VERSION 5.7 ;
  NOWIREEXTENSIONATPIN ON ;
  DIVIDERCHAR "/" ;
  BUSBITCHARS "[]" ;
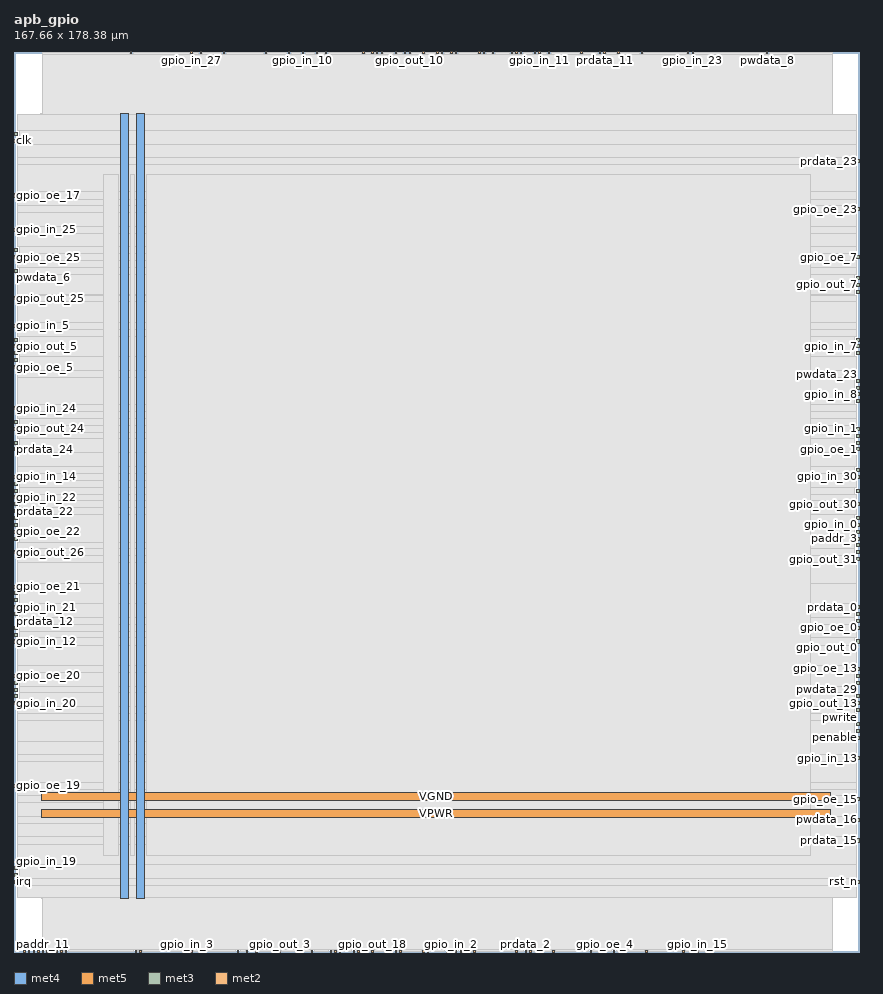
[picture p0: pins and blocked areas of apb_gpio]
MACRO apb_gpio
  CLASS BLOCK ;
  FOREIGN apb_gpio ;
  ORIGIN 0.000 0.000 ;
  SIZE 167.660 BY 178.380 ;
  PIN VGND
    DIRECTION INOUT ;
    USE GROUND ;
    PORT
      LAYER met4 ;
        RECT 24.340 10.640 25.940 166.160 ;
    END
    PORT
      LAYER met5 ;
        RECT 5.520 30.030 161.920 31.630 ;
    END
  END VGND
  PIN VPWR
    DIRECTION INOUT ;
    USE POWER ;
    PORT
      LAYER met4 ;
        RECT 21.040 10.640 22.640 166.160 ;
    END
    PORT
      LAYER met5 ;
        RECT 5.520 26.730 161.920 28.330 ;
    END
  END VPWR
  PIN clk
    DIRECTION INPUT ;
    USE SIGNAL ;
    ANTENNAGATEAREA 1.286700 ;
    ANTENNADIFFAREA 0.434700 ;
    PORT
      LAYER met3 ;
        RECT 0.000 160.520 0.600 161.120 ;
    END
  END clk
  PIN gpio_in_0
    DIRECTION INPUT ;
    USE SIGNAL ;
    ANTENNAGATEAREA 0.647700 ;
    ANTENNADIFFAREA 0.434700 ;
    PORT
      LAYER met3 ;
        RECT 167.060 84.360 167.660 84.960 ;
    END
  END gpio_in_0
  PIN gpio_in_1
    DIRECTION INPUT ;
    USE SIGNAL ;
    ANTENNAGATEAREA 0.647700 ;
    ANTENNADIFFAREA 0.434700 ;
    PORT
      LAYER met3 ;
        RECT 167.060 103.400 167.660 104.000 ;
    END
  END gpio_in_1
  PIN gpio_in_10
    DIRECTION INPUT ;
    USE SIGNAL ;
    ANTENNAGATEAREA 0.647700 ;
    ANTENNADIFFAREA 0.434700 ;
    PORT
      LAYER met2 ;
        RECT 57.130 178.100 57.410 178.380 ;
    END
  END gpio_in_10
  PIN gpio_in_11
    DIRECTION INPUT ;
    USE SIGNAL ;
    ANTENNAGATEAREA 0.647700 ;
    ANTENNADIFFAREA 0.434700 ;
    PORT
      LAYER met2 ;
        RECT 104.050 178.100 104.330 178.380 ;
    END
  END gpio_in_11
  PIN gpio_in_12
    DIRECTION INPUT ;
    USE SIGNAL ;
    ANTENNAGATEAREA 0.647700 ;
    ANTENNADIFFAREA 0.434700 ;
    PORT
      LAYER met3 ;
        RECT 0.000 61.240 0.600 61.840 ;
    END
  END gpio_in_12
  PIN gpio_in_13
    DIRECTION INPUT ;
    USE SIGNAL ;
    ANTENNAGATEAREA 0.647700 ;
    ANTENNADIFFAREA 0.434700 ;
    PORT
      LAYER met3 ;
        RECT 167.060 38.120 167.660 38.720 ;
    END
  END gpio_in_13
  PIN gpio_in_14
    DIRECTION INPUT ;
    USE SIGNAL ;
    ANTENNAGATEAREA 0.647700 ;
    ANTENNADIFFAREA 0.434700 ;
    PORT
      LAYER met3 ;
        RECT 0.000 93.880 0.600 94.480 ;
    END
  END gpio_in_14
  PIN gpio_in_15
    DIRECTION INPUT ;
    USE SIGNAL ;
    ANTENNAGATEAREA 0.647700 ;
    ANTENNADIFFAREA 0.434700 ;
    PORT
      LAYER met2 ;
        RECT 135.330 0.000 135.610 0.280 ;
    END
  END gpio_in_15
  PIN gpio_in_16
    DIRECTION INPUT ;
    USE SIGNAL ;
    ANTENNAGATEAREA 0.647700 ;
    ANTENNADIFFAREA 0.434700 ;
    PORT
      LAYER met3 ;
        RECT 0.000 121.080 0.600 121.680 ;
    END
  END gpio_in_16
  PIN gpio_in_17
    DIRECTION INPUT ;
    USE SIGNAL ;
    ANTENNAGATEAREA 0.647700 ;
    ANTENNADIFFAREA 0.434700 ;
    PORT
      LAYER met3 ;
        RECT 0.000 161.880 0.600 162.480 ;
    END
  END gpio_in_17
  PIN gpio_in_18
    DIRECTION INPUT ;
    USE SIGNAL ;
    ANTENNAGATEAREA 0.647700 ;
    ANTENNADIFFAREA 0.434700 ;
    PORT
      LAYER met2 ;
        RECT 58.970 0.000 59.250 0.280 ;
    END
  END gpio_in_18
  PIN gpio_in_19
    DIRECTION INPUT ;
    USE SIGNAL ;
    ANTENNAGATEAREA 0.647700 ;
    ANTENNADIFFAREA 0.434700 ;
    PORT
      LAYER met3 ;
        RECT 0.000 16.360 0.600 16.960 ;
    END
  END gpio_in_19
  PIN gpio_in_2
    DIRECTION INPUT ;
    USE SIGNAL ;
    ANTENNAGATEAREA 0.647700 ;
    ANTENNADIFFAREA 0.434700 ;
    PORT
      LAYER met2 ;
        RECT 86.570 0.000 86.850 0.280 ;
    END
  END gpio_in_2
  PIN gpio_in_20
    DIRECTION INPUT ;
    USE SIGNAL ;
    ANTENNAGATEAREA 0.647700 ;
    ANTENNADIFFAREA 0.434700 ;
    PORT
      LAYER met3 ;
        RECT 0.000 49.000 0.600 49.600 ;
    END
  END gpio_in_20
  PIN gpio_in_21
    DIRECTION INPUT ;
    USE SIGNAL ;
    ANTENNAGATEAREA 0.647700 ;
    ANTENNADIFFAREA 0.434700 ;
    PORT
      LAYER met3 ;
        RECT 0.000 68.040 0.600 68.640 ;
    END
  END gpio_in_21
  PIN gpio_in_22
    DIRECTION INPUT ;
    USE SIGNAL ;
    ANTENNAGATEAREA 0.647700 ;
    ANTENNADIFFAREA 0.434700 ;
    PORT
      LAYER met3 ;
        RECT 0.000 91.160 0.600 91.760 ;
    END
  END gpio_in_22
  PIN gpio_in_23
    DIRECTION INPUT ;
    USE SIGNAL ;
    ANTENNAGATEAREA 0.647700 ;
    ANTENNADIFFAREA 0.434700 ;
    PORT
      LAYER met2 ;
        RECT 134.410 178.100 134.690 178.380 ;
    END
  END gpio_in_23
  PIN gpio_in_24
    DIRECTION INPUT ;
    USE SIGNAL ;
    ANTENNAGATEAREA 0.647700 ;
    ANTENNADIFFAREA 0.434700 ;
    PORT
      LAYER met3 ;
        RECT 0.000 107.480 0.600 108.080 ;
    END
  END gpio_in_24
  PIN gpio_in_25
    DIRECTION INPUT ;
    USE SIGNAL ;
    ANTENNAGATEAREA 0.647700 ;
    ANTENNADIFFAREA 0.434700 ;
    PORT
      LAYER met3 ;
        RECT 0.000 142.840 0.600 143.440 ;
    END
  END gpio_in_25
  PIN gpio_in_26
    DIRECTION INPUT ;
    USE SIGNAL ;
    ANTENNAGATEAREA 0.647700 ;
    ANTENNADIFFAREA 0.434700 ;
    PORT
      LAYER met3 ;
        RECT 0.000 89.800 0.600 90.400 ;
    END
  END gpio_in_26
  PIN gpio_in_27
    DIRECTION INPUT ;
    USE SIGNAL ;
    ANTENNAGATEAREA 0.647700 ;
    ANTENNADIFFAREA 0.434700 ;
    PORT
      LAYER met2 ;
        RECT 35.050 178.100 35.330 178.380 ;
    END
  END gpio_in_27
  PIN gpio_in_28
    DIRECTION INPUT ;
    USE SIGNAL ;
    ANTENNAGATEAREA 0.647700 ;
    ANTENNADIFFAREA 0.434700 ;
    PORT
      LAYER met2 ;
        RECT 84.730 178.100 85.010 178.380 ;
    END
  END gpio_in_28
  PIN gpio_in_29
    DIRECTION INPUT ;
    USE SIGNAL ;
    ANTENNAGATEAREA 0.647700 ;
    ANTENNADIFFAREA 0.434700 ;
    PORT
      LAYER met2 ;
        RECT 86.570 178.100 86.850 178.380 ;
    END
  END gpio_in_29
  PIN gpio_in_3
    DIRECTION INPUT ;
    USE SIGNAL ;
    ANTENNAGATEAREA 0.647700 ;
    ANTENNADIFFAREA 0.434700 ;
    PORT
      LAYER met2 ;
        RECT 34.130 0.000 34.410 0.280 ;
    END
  END gpio_in_3
  PIN gpio_in_30
    DIRECTION INPUT ;
    USE SIGNAL ;
    ANTENNAGATEAREA 0.647700 ;
    ANTENNADIFFAREA 0.434700 ;
    PORT
      LAYER met3 ;
        RECT 167.060 93.880 167.660 94.480 ;
    END
  END gpio_in_30
  PIN gpio_in_31
    DIRECTION INPUT ;
    USE SIGNAL ;
    ANTENNAGATEAREA 0.647700 ;
    ANTENNADIFFAREA 0.434700 ;
    PORT
      LAYER met2 ;
        RECT 75.530 0.000 75.810 0.280 ;
    END
  END gpio_in_31
  PIN gpio_in_4
    DIRECTION INPUT ;
    USE SIGNAL ;
    ANTENNAGATEAREA 0.647700 ;
    ANTENNADIFFAREA 0.434700 ;
    PORT
      LAYER met2 ;
        RECT 114.170 0.000 114.450 0.280 ;
    END
  END gpio_in_4
  PIN gpio_in_5
    DIRECTION INPUT ;
    USE SIGNAL ;
    ANTENNAGATEAREA 0.647700 ;
    ANTENNADIFFAREA 0.434700 ;
    PORT
      LAYER met3 ;
        RECT 0.000 123.800 0.600 124.400 ;
    END
  END gpio_in_5
  PIN gpio_in_6
    DIRECTION INPUT ;
    USE SIGNAL ;
    ANTENNAGATEAREA 0.647700 ;
    ANTENNADIFFAREA 0.434700 ;
    PORT
      LAYER met2 ;
        RECT 76.450 0.000 76.730 0.280 ;
    END
  END gpio_in_6
  PIN gpio_in_7
    DIRECTION INPUT ;
    USE SIGNAL ;
    ANTENNAGATEAREA 0.647700 ;
    ANTENNADIFFAREA 0.434700 ;
    PORT
      LAYER met3 ;
        RECT 167.060 119.720 167.660 120.320 ;
    END
  END gpio_in_7
  PIN gpio_in_8
    DIRECTION INPUT ;
    USE SIGNAL ;
    ANTENNAGATEAREA 0.647700 ;
    ANTENNADIFFAREA 0.434700 ;
    PORT
      LAYER met3 ;
        RECT 167.060 110.200 167.660 110.800 ;
    END
  END gpio_in_8
  PIN gpio_in_9
    DIRECTION INPUT ;
    USE SIGNAL ;
    ANTENNAGATEAREA 0.647700 ;
    ANTENNADIFFAREA 0.434700 ;
    PORT
      LAYER met2 ;
        RECT 90.250 0.000 90.530 0.280 ;
    END
  END gpio_in_9
  PIN gpio_oe_0
    DIRECTION OUTPUT ;
    USE SIGNAL ;
    ANTENNAGATEAREA 0.434700 ;
    ANTENNADIFFAREA 1.137600 ;
    PORT
      LAYER met3 ;
        RECT 167.060 63.960 167.660 64.560 ;
    END
  END gpio_oe_0
  PIN gpio_oe_1
    DIRECTION OUTPUT ;
    USE SIGNAL ;
    ANTENNAGATEAREA 0.434700 ;
    ANTENNADIFFAREA 1.137600 ;
    PORT
      LAYER met3 ;
        RECT 167.060 100.680 167.660 101.280 ;
    END
  END gpio_oe_1
  PIN gpio_oe_10
    DIRECTION OUTPUT ;
    USE SIGNAL ;
    ANTENNAGATEAREA 0.434700 ;
    ANTENNADIFFAREA 1.137600 ;
    PORT
      LAYER met2 ;
        RECT 71.850 178.100 72.130 178.380 ;
    END
  END gpio_oe_10
  PIN gpio_oe_11
    DIRECTION OUTPUT ;
    USE SIGNAL ;
    ANTENNAGATEAREA 0.434700 ;
    ANTENNADIFFAREA 1.137600 ;
    PORT
      LAYER met2 ;
        RECT 116.010 178.100 116.290 178.380 ;
    END
  END gpio_oe_11
  PIN gpio_oe_12
    DIRECTION OUTPUT ;
    USE SIGNAL ;
    ANTENNAGATEAREA 0.434700 ;
    ANTENNADIFFAREA 1.137600 ;
    PORT
      LAYER met3 ;
        RECT 0.000 69.400 0.600 70.000 ;
    END
  END gpio_oe_12
  PIN gpio_oe_13
    DIRECTION OUTPUT ;
    USE SIGNAL ;
    ANTENNAGATEAREA 0.434700 ;
    ANTENNADIFFAREA 1.137600 ;
    PORT
      LAYER met3 ;
        RECT 167.060 55.800 167.660 56.400 ;
    END
  END gpio_oe_13
  PIN gpio_oe_14
    DIRECTION OUTPUT ;
    USE SIGNAL ;
    ANTENNAGATEAREA 0.434700 ;
    ANTENNADIFFAREA 1.137600 ;
    PORT
      LAYER met2 ;
        RECT 98.530 178.100 98.810 178.380 ;
    END
  END gpio_oe_14
  PIN gpio_oe_15
    DIRECTION OUTPUT ;
    USE SIGNAL ;
    ANTENNAGATEAREA 0.434700 ;
    ANTENNADIFFAREA 1.137600 ;
    PORT
      LAYER met3 ;
        RECT 167.060 29.960 167.660 30.560 ;
    END
  END gpio_oe_15
  PIN gpio_oe_16
    DIRECTION OUTPUT ;
    USE SIGNAL ;
    ANTENNAGATEAREA 0.434700 ;
    ANTENNADIFFAREA 1.137600 ;
    PORT
      LAYER met2 ;
        RECT 75.530 178.100 75.810 178.380 ;
    END
  END gpio_oe_16
  PIN gpio_oe_17
    DIRECTION OUTPUT ;
    USE SIGNAL ;
    ANTENNAGATEAREA 0.434700 ;
    ANTENNADIFFAREA 1.137600 ;
    PORT
      LAYER met3 ;
        RECT 0.000 149.640 0.600 150.240 ;
    END
  END gpio_oe_17
  PIN gpio_oe_18
    DIRECTION OUTPUT ;
    USE SIGNAL ;
    ANTENNAGATEAREA 0.434700 ;
    ANTENNADIFFAREA 1.137600 ;
    PORT
      LAYER met2 ;
        RECT 63.570 0.000 63.850 0.280 ;
    END
  END gpio_oe_18
  PIN gpio_oe_19
    DIRECTION OUTPUT ;
    USE SIGNAL ;
    ANTENNAGATEAREA 0.434700 ;
    ANTENNADIFFAREA 1.137600 ;
    PORT
      LAYER met3 ;
        RECT 0.000 32.680 0.600 33.280 ;
    END
  END gpio_oe_19
  PIN gpio_oe_2
    DIRECTION OUTPUT ;
    USE SIGNAL ;
    ANTENNAGATEAREA 0.434700 ;
    ANTENNADIFFAREA 1.137600 ;
    PORT
      LAYER met3 ;
        RECT 167.060 65.320 167.660 65.920 ;
    END
  END gpio_oe_2
  PIN gpio_oe_20
    DIRECTION OUTPUT ;
    USE SIGNAL ;
    ANTENNAGATEAREA 0.434700 ;
    ANTENNADIFFAREA 1.137600 ;
    PORT
      LAYER met3 ;
        RECT 0.000 54.440 0.600 55.040 ;
    END
  END gpio_oe_20
  PIN gpio_oe_21
    DIRECTION OUTPUT ;
    USE SIGNAL ;
    ANTENNAGATEAREA 0.434700 ;
    ANTENNADIFFAREA 1.137600 ;
    PORT
      LAYER met3 ;
        RECT 0.000 72.120 0.600 72.720 ;
    END
  END gpio_oe_21
  PIN gpio_oe_22
    DIRECTION OUTPUT ;
    USE SIGNAL ;
    ANTENNAGATEAREA 0.434700 ;
    ANTENNADIFFAREA 1.137600 ;
    PORT
      LAYER met3 ;
        RECT 0.000 83.000 0.600 83.600 ;
    END
  END gpio_oe_22
  PIN gpio_oe_23
    DIRECTION OUTPUT ;
    USE SIGNAL ;
    ANTENNAGATEAREA 0.434700 ;
    ANTENNADIFFAREA 1.137600 ;
    PORT
      LAYER met3 ;
        RECT 167.060 146.920 167.660 147.520 ;
    END
  END gpio_oe_23
  PIN gpio_oe_24
    DIRECTION OUTPUT ;
    USE SIGNAL ;
    ANTENNAGATEAREA 0.434700 ;
    ANTENNADIFFAREA 1.137600 ;
    PORT
      LAYER met3 ;
        RECT 0.000 99.320 0.600 99.920 ;
    END
  END gpio_oe_24
  PIN gpio_oe_25
    DIRECTION OUTPUT ;
    USE SIGNAL ;
    ANTENNAGATEAREA 0.434700 ;
    ANTENNADIFFAREA 1.137600 ;
    PORT
      LAYER met3 ;
        RECT 0.000 137.400 0.600 138.000 ;
    END
  END gpio_oe_25
  PIN gpio_oe_26
    DIRECTION OUTPUT ;
    USE SIGNAL ;
    ANTENNAGATEAREA 0.434700 ;
    ANTENNADIFFAREA 1.137600 ;
    PORT
      LAYER met3 ;
        RECT 0.000 87.080 0.600 87.680 ;
    END
  END gpio_oe_26
  PIN gpio_oe_27
    DIRECTION OUTPUT ;
    USE SIGNAL ;
    ANTENNAGATEAREA 0.434700 ;
    ANTENNADIFFAREA 1.137600 ;
    PORT
      LAYER met2 ;
        RECT 54.370 178.100 54.650 178.380 ;
    END
  END gpio_oe_27
  PIN gpio_oe_28
    DIRECTION OUTPUT ;
    USE SIGNAL ;
    ANTENNAGATEAREA 0.434700 ;
    ANTENNADIFFAREA 1.137600 ;
    PORT
      LAYER met3 ;
        RECT 167.060 108.840 167.660 109.440 ;
    END
  END gpio_oe_28
  PIN gpio_oe_29
    DIRECTION OUTPUT ;
    USE SIGNAL ;
    ANTENNAGATEAREA 0.434700 ;
    ANTENNADIFFAREA 1.137600 ;
    PORT
      LAYER met2 ;
        RECT 92.090 178.100 92.370 178.380 ;
    END
  END gpio_oe_29
  PIN gpio_oe_3
    DIRECTION OUTPUT ;
    USE SIGNAL ;
    ANTENNAGATEAREA 0.434700 ;
    ANTENNADIFFAREA 1.137600 ;
    PORT
      LAYER met2 ;
        RECT 44.250 0.000 44.530 0.280 ;
    END
  END gpio_oe_3
  PIN gpio_oe_30
    DIRECTION OUTPUT ;
    USE SIGNAL ;
    ANTENNAGATEAREA 0.434700 ;
    ANTENNADIFFAREA 1.137600 ;
    PORT
      LAYER met3 ;
        RECT 167.060 85.720 167.660 86.320 ;
    END
  END gpio_oe_30
  PIN gpio_oe_31
    DIRECTION OUTPUT ;
    USE SIGNAL ;
    ANTENNAGATEAREA 0.434700 ;
    ANTENNADIFFAREA 1.137600 ;
    PORT
      LAYER met2 ;
        RECT 88.410 0.000 88.690 0.280 ;
    END
  END gpio_oe_31
  PIN gpio_oe_4
    DIRECTION OUTPUT ;
    USE SIGNAL ;
    ANTENNAGATEAREA 0.434700 ;
    ANTENNADIFFAREA 1.137600 ;
    PORT
      LAYER met2 ;
        RECT 116.930 0.000 117.210 0.280 ;
    END
  END gpio_oe_4
  PIN gpio_oe_5
    DIRECTION OUTPUT ;
    USE SIGNAL ;
    ANTENNAGATEAREA 0.434700 ;
    ANTENNADIFFAREA 1.137600 ;
    PORT
      LAYER met3 ;
        RECT 0.000 115.640 0.600 116.240 ;
    END
  END gpio_oe_5
  PIN gpio_oe_6
    DIRECTION OUTPUT ;
    USE SIGNAL ;
    ANTENNAGATEAREA 0.434700 ;
    ANTENNADIFFAREA 1.137600 ;
    PORT
      LAYER met2 ;
        RECT 81.050 0.000 81.330 0.280 ;
    END
  END gpio_oe_6
  PIN gpio_oe_7
    DIRECTION OUTPUT ;
    USE SIGNAL ;
    ANTENNAGATEAREA 0.434700 ;
    ANTENNADIFFAREA 1.137600 ;
    PORT
      LAYER met3 ;
        RECT 167.060 137.400 167.660 138.000 ;
    END
  END gpio_oe_7
  PIN gpio_oe_8
    DIRECTION OUTPUT ;
    USE SIGNAL ;
    ANTENNAGATEAREA 0.434700 ;
    ANTENNADIFFAREA 1.137600 ;
    PORT
      LAYER met3 ;
        RECT 167.060 121.080 167.660 121.680 ;
    END
  END gpio_oe_8
  PIN gpio_oe_9
    DIRECTION OUTPUT ;
    USE SIGNAL ;
    ANTENNAGATEAREA 0.434700 ;
    ANTENNADIFFAREA 1.137600 ;
    PORT
      LAYER met2 ;
        RECT 99.450 0.000 99.730 0.280 ;
    END
  END gpio_oe_9
  PIN gpio_out_0
    DIRECTION OUTPUT ;
    USE SIGNAL ;
    ANTENNAGATEAREA 0.434700 ;
    ANTENNADIFFAREA 1.137600 ;
    PORT
      LAYER met3 ;
        RECT 167.060 61.240 167.660 61.840 ;
    END
  END gpio_out_0
  PIN gpio_out_1
    DIRECTION OUTPUT ;
    USE SIGNAL ;
    ANTENNAGATEAREA 0.434700 ;
    ANTENNADIFFAREA 1.137600 ;
    PORT
      LAYER met3 ;
        RECT 167.060 99.320 167.660 99.920 ;
    END
  END gpio_out_1
  PIN gpio_out_10
    DIRECTION OUTPUT ;
    USE SIGNAL ;
    ANTENNAGATEAREA 0.434700 ;
    ANTENNADIFFAREA 1.137600 ;
    PORT
      LAYER met2 ;
        RECT 78.290 178.100 78.570 178.380 ;
    END
  END gpio_out_10
  PIN gpio_out_11
    DIRECTION OUTPUT ;
    USE SIGNAL ;
    ANTENNAGATEAREA 0.434700 ;
    ANTENNADIFFAREA 1.137600 ;
    PORT
      LAYER met2 ;
        RECT 119.690 178.100 119.970 178.380 ;
    END
  END gpio_out_11
  PIN gpio_out_12
    DIRECTION OUTPUT ;
    USE SIGNAL ;
    ANTENNAGATEAREA 0.434700 ;
    ANTENNADIFFAREA 1.137600 ;
    PORT
      LAYER met2 ;
        RECT 68.170 0.000 68.450 0.280 ;
    END
  END gpio_out_12
  PIN gpio_out_13
    DIRECTION OUTPUT ;
    USE SIGNAL ;
    ANTENNAGATEAREA 0.434700 ;
    ANTENNADIFFAREA 1.137600 ;
    PORT
      LAYER met3 ;
        RECT 167.060 49.000 167.660 49.600 ;
    END
  END gpio_out_13
  PIN gpio_out_14
    DIRECTION OUTPUT ;
    USE SIGNAL ;
    ANTENNAGATEAREA 0.434700 ;
    ANTENNADIFFAREA 1.137600 ;
    PORT
      LAYER met2 ;
        RECT 81.050 178.100 81.330 178.380 ;
    END
  END gpio_out_14
  PIN gpio_out_15
    DIRECTION OUTPUT ;
    USE SIGNAL ;
    ANTENNAGATEAREA 0.434700 ;
    ANTENNADIFFAREA 1.137600 ;
    PORT
      LAYER met2 ;
        RECT 132.570 0.000 132.850 0.280 ;
    END
  END gpio_out_15
  PIN gpio_out_16
    DIRECTION OUTPUT ;
    USE SIGNAL ;
    ANTENNAGATEAREA 0.434700 ;
    ANTENNADIFFAREA 1.137600 ;
    PORT
      LAYER met2 ;
        RECT 70.930 178.100 71.210 178.380 ;
    END
  END gpio_out_16
  PIN gpio_out_17
    DIRECTION OUTPUT ;
    USE SIGNAL ;
    ANTENNAGATEAREA 0.434700 ;
    ANTENNADIFFAREA 1.137600 ;
    PORT
      LAYER met2 ;
        RECT 36.890 178.100 37.170 178.380 ;
    END
  END gpio_out_17
  PIN gpio_out_18
    DIRECTION OUTPUT ;
    USE SIGNAL ;
    ANTENNAGATEAREA 0.434700 ;
    ANTENNADIFFAREA 1.137600 ;
    PORT
      LAYER met2 ;
        RECT 70.930 0.000 71.210 0.280 ;
    END
  END gpio_out_18
  PIN gpio_out_19
    DIRECTION OUTPUT ;
    USE SIGNAL ;
    ANTENNAGATEAREA 0.434700 ;
    ANTENNADIFFAREA 1.137600 ;
    PORT
      LAYER met2 ;
        RECT 35.050 0.000 35.330 0.280 ;
    END
  END gpio_out_19
  PIN gpio_out_2
    DIRECTION OUTPUT ;
    USE SIGNAL ;
    ANTENNAGATEAREA 0.434700 ;
    ANTENNADIFFAREA 1.137600 ;
    PORT
      LAYER met3 ;
        RECT 167.060 54.440 167.660 55.040 ;
    END
  END gpio_out_2
  PIN gpio_out_20
    DIRECTION OUTPUT ;
    USE SIGNAL ;
    ANTENNAGATEAREA 0.434700 ;
    ANTENNADIFFAREA 1.137600 ;
    PORT
      LAYER met3 ;
        RECT 0.000 51.720 0.600 52.320 ;
    END
  END gpio_out_20
  PIN gpio_out_21
    DIRECTION OUTPUT ;
    USE SIGNAL ;
    ANTENNAGATEAREA 0.434700 ;
    ANTENNADIFFAREA 1.137600 ;
    PORT
      LAYER met3 ;
        RECT 0.000 62.600 0.600 63.200 ;
    END
  END gpio_out_21
  PIN gpio_out_22
    DIRECTION OUTPUT ;
    USE SIGNAL ;
    ANTENNAGATEAREA 0.434700 ;
    ANTENNADIFFAREA 1.137600 ;
    PORT
      LAYER met3 ;
        RECT 0.000 92.520 0.600 93.120 ;
    END
  END gpio_out_22
  PIN gpio_out_23
    DIRECTION OUTPUT ;
    USE SIGNAL ;
    ANTENNAGATEAREA 0.434700 ;
    ANTENNADIFFAREA 1.137600 ;
    PORT
      LAYER met2 ;
        RECT 133.490 178.100 133.770 178.380 ;
    END
  END gpio_out_23
  PIN gpio_out_24
    DIRECTION OUTPUT ;
    USE SIGNAL ;
    ANTENNAGATEAREA 0.434700 ;
    ANTENNADIFFAREA 1.137600 ;
    PORT
      LAYER met3 ;
        RECT 0.000 103.400 0.600 104.000 ;
    END
  END gpio_out_24
  PIN gpio_out_25
    DIRECTION OUTPUT ;
    USE SIGNAL ;
    ANTENNAGATEAREA 0.434700 ;
    ANTENNADIFFAREA 1.137600 ;
    PORT
      LAYER met3 ;
        RECT 0.000 129.240 0.600 129.840 ;
    END
  END gpio_out_25
  PIN gpio_out_26
    DIRECTION OUTPUT ;
    USE SIGNAL ;
    ANTENNAGATEAREA 0.434700 ;
    ANTENNADIFFAREA 1.137600 ;
    PORT
      LAYER met3 ;
        RECT 0.000 78.920 0.600 79.520 ;
    END
  END gpio_out_26
  PIN gpio_out_27
    DIRECTION OUTPUT ;
    USE SIGNAL ;
    ANTENNAGATEAREA 0.434700 ;
    ANTENNADIFFAREA 1.137600 ;
    PORT
      LAYER met2 ;
        RECT 59.890 178.100 60.170 178.380 ;
    END
  END gpio_out_27
  PIN gpio_out_28
    DIRECTION OUTPUT ;
    USE SIGNAL ;
    ANTENNAGATEAREA 0.434700 ;
    ANTENNADIFFAREA 1.137600 ;
    PORT
      LAYER met2 ;
        RECT 105.890 178.100 106.170 178.380 ;
    END
  END gpio_out_28
  PIN gpio_out_29
    DIRECTION OUTPUT ;
    USE SIGNAL ;
    ANTENNAGATEAREA 0.434700 ;
    ANTENNADIFFAREA 1.137600 ;
    PORT
      LAYER met2 ;
        RECT 99.450 178.100 99.730 178.380 ;
    END
  END gpio_out_29
  PIN gpio_out_3
    DIRECTION OUTPUT ;
    USE SIGNAL ;
    ANTENNAGATEAREA 0.434700 ;
    ANTENNADIFFAREA 1.137600 ;
    PORT
      LAYER met2 ;
        RECT 52.530 0.000 52.810 0.280 ;
    END
  END gpio_out_3
  PIN gpio_out_30
    DIRECTION OUTPUT ;
    USE SIGNAL ;
    ANTENNAGATEAREA 0.434700 ;
    ANTENNADIFFAREA 1.137600 ;
    PORT
      LAYER met3 ;
        RECT 167.060 88.440 167.660 89.040 ;
    END
  END gpio_out_30
  PIN gpio_out_31
    DIRECTION OUTPUT ;
    USE SIGNAL ;
    ANTENNAGATEAREA 0.434700 ;
    ANTENNADIFFAREA 1.137600 ;
    PORT
      LAYER met3 ;
        RECT 167.060 77.560 167.660 78.160 ;
    END
  END gpio_out_31
  PIN gpio_out_4
    DIRECTION OUTPUT ;
    USE SIGNAL ;
    ANTENNAGATEAREA 0.434700 ;
    ANTENNADIFFAREA 1.137600 ;
    PORT
      LAYER met2 ;
        RECT 125.210 0.000 125.490 0.280 ;
    END
  END gpio_out_4
  PIN gpio_out_5
    DIRECTION OUTPUT ;
    USE SIGNAL ;
    ANTENNAGATEAREA 0.434700 ;
    ANTENNADIFFAREA 1.137600 ;
    PORT
      LAYER met3 ;
        RECT 0.000 119.720 0.600 120.320 ;
    END
  END gpio_out_5
  PIN gpio_out_6
    DIRECTION OUTPUT ;
    USE SIGNAL ;
    ANTENNAGATEAREA 0.434700 ;
    ANTENNADIFFAREA 1.137600 ;
    PORT
      LAYER met2 ;
        RECT 89.330 0.000 89.610 0.280 ;
    END
  END gpio_out_6
  PIN gpio_out_7
    DIRECTION OUTPUT ;
    USE SIGNAL ;
    ANTENNAGATEAREA 0.434700 ;
    ANTENNADIFFAREA 1.137600 ;
    PORT
      LAYER met3 ;
        RECT 167.060 131.960 167.660 132.560 ;
    END
  END gpio_out_7
  PIN gpio_out_8
    DIRECTION OUTPUT ;
    USE SIGNAL ;
    ANTENNAGATEAREA 0.434700 ;
    ANTENNADIFFAREA 1.137600 ;
    PORT
      LAYER met3 ;
        RECT 167.060 111.560 167.660 112.160 ;
    END
  END gpio_out_8
  PIN gpio_out_9
    DIRECTION OUTPUT ;
    USE SIGNAL ;
    ANTENNAGATEAREA 0.434700 ;
    ANTENNADIFFAREA 1.137600 ;
    PORT
      LAYER met2 ;
        RECT 106.810 0.000 107.090 0.280 ;
    END
  END gpio_out_9
  PIN irq
    DIRECTION OUTPUT ;
    USE SIGNAL ;
    ANTENNAGATEAREA 0.434700 ;
    ANTENNADIFFAREA 0.775300 ;
    PORT
      LAYER met3 ;
        RECT 0.000 13.640 0.600 14.240 ;
    END
  END irq
  PIN paddr_0
    DIRECTION INPUT ;
    USE SIGNAL ;
    PORT
      LAYER met2 ;
        RECT 1.930 0.000 2.210 0.280 ;
    END
  END paddr_0
  PIN paddr_1
    DIRECTION INPUT ;
    USE SIGNAL ;
    PORT
      LAYER met2 ;
        RECT 2.850 0.000 3.130 0.280 ;
    END
  END paddr_1
  PIN paddr_10
    DIRECTION INPUT ;
    USE SIGNAL ;
    PORT
      LAYER met2 ;
        RECT 3.770 0.000 4.050 0.280 ;
    END
  END paddr_10
  PIN paddr_11
    DIRECTION INPUT ;
    USE SIGNAL ;
    PORT
      LAYER met2 ;
        RECT 4.690 0.000 4.970 0.280 ;
    END
  END paddr_11
  PIN paddr_2
    DIRECTION INPUT ;
    USE SIGNAL ;
    ANTENNAGATEAREA 0.647700 ;
    ANTENNADIFFAREA 0.434700 ;
    PORT
      LAYER met3 ;
        RECT 167.060 78.920 167.660 79.520 ;
    END
  END paddr_2
  PIN paddr_3
    DIRECTION INPUT ;
    USE SIGNAL ;
    ANTENNAGATEAREA 0.647700 ;
    ANTENNADIFFAREA 0.434700 ;
    PORT
      LAYER met3 ;
        RECT 167.060 80.280 167.660 80.880 ;
    END
  END paddr_3
  PIN paddr_4
    DIRECTION INPUT ;
    USE SIGNAL ;
    ANTENNAGATEAREA 0.647700 ;
    ANTENNADIFFAREA 0.434700 ;
    PORT
      LAYER met3 ;
        RECT 167.060 81.640 167.660 82.240 ;
    END
  END paddr_4
  PIN paddr_5
    DIRECTION INPUT ;
    USE SIGNAL ;
    PORT
      LAYER met2 ;
        RECT 5.610 0.000 5.890 0.280 ;
    END
  END paddr_5
  PIN paddr_6
    DIRECTION INPUT ;
    USE SIGNAL ;
    PORT
      LAYER met2 ;
        RECT 6.530 0.000 6.810 0.280 ;
    END
  END paddr_6
  PIN paddr_7
    DIRECTION INPUT ;
    USE SIGNAL ;
    PORT
      LAYER met2 ;
        RECT 7.450 0.000 7.730 0.280 ;
    END
  END paddr_7
  PIN paddr_8
    DIRECTION INPUT ;
    USE SIGNAL ;
    PORT
      LAYER met2 ;
        RECT 8.370 0.000 8.650 0.280 ;
    END
  END paddr_8
  PIN paddr_9
    DIRECTION INPUT ;
    USE SIGNAL ;
    PORT
      LAYER met2 ;
        RECT 9.290 0.000 9.570 0.280 ;
    END
  END paddr_9
  PIN penable
    DIRECTION INPUT ;
    USE SIGNAL ;
    ANTENNAGATEAREA 0.647700 ;
    ANTENNADIFFAREA 0.434700 ;
    PORT
      LAYER met3 ;
        RECT 167.060 42.200 167.660 42.800 ;
    END
  END penable
  PIN prdata_0
    DIRECTION OUTPUT ;
    USE SIGNAL ;
    ANTENNAGATEAREA 0.434700 ;
    ANTENNADIFFAREA 1.137600 ;
    PORT
      LAYER met3 ;
        RECT 167.060 68.040 167.660 68.640 ;
    END
  END prdata_0
  PIN prdata_1
    DIRECTION OUTPUT ;
    USE SIGNAL ;
    ANTENNAGATEAREA 0.434700 ;
    ANTENNADIFFAREA 0.832300 ;
    PORT
      LAYER met3 ;
        RECT 167.060 102.040 167.660 102.640 ;
    END
  END prdata_1
  PIN prdata_10
    DIRECTION OUTPUT ;
    USE SIGNAL ;
    ANTENNAGATEAREA 0.560700 ;
    ANTENNADIFFAREA 0.863700 ;
    PORT
      LAYER met2 ;
        RECT 72.770 178.100 73.050 178.380 ;
    END
  END prdata_10
  PIN prdata_11
    DIRECTION OUTPUT ;
    USE SIGNAL ;
    ANTENNAGATEAREA 0.434700 ;
    ANTENNADIFFAREA 1.137600 ;
    PORT
      LAYER met2 ;
        RECT 116.930 178.100 117.210 178.380 ;
    END
  END prdata_11
  PIN prdata_12
    DIRECTION OUTPUT ;
    USE SIGNAL ;
    ANTENNAGATEAREA 0.434700 ;
    ANTENNADIFFAREA 0.832300 ;
    PORT
      LAYER met3 ;
        RECT 0.000 63.960 0.600 64.560 ;
    END
  END prdata_12
  PIN prdata_13
    DIRECTION OUTPUT ;
    USE SIGNAL ;
    ANTENNAGATEAREA 0.434700 ;
    ANTENNADIFFAREA 1.137600 ;
    PORT
      LAYER met3 ;
        RECT 167.060 50.360 167.660 50.960 ;
    END
  END prdata_13
  PIN prdata_14
    DIRECTION OUTPUT ;
    USE SIGNAL ;
    ANTENNAGATEAREA 0.434700 ;
    ANTENNADIFFAREA 0.832300 ;
    PORT
      LAYER met2 ;
        RECT 87.490 178.100 87.770 178.380 ;
    END
  END prdata_14
  PIN prdata_15
    DIRECTION OUTPUT ;
    USE SIGNAL ;
    ANTENNAGATEAREA 0.434700 ;
    ANTENNADIFFAREA 1.137600 ;
    PORT
      LAYER met3 ;
        RECT 167.060 21.800 167.660 22.400 ;
    END
  END prdata_15
  PIN prdata_16
    DIRECTION OUTPUT ;
    USE SIGNAL ;
    ANTENNAGATEAREA 0.434700 ;
    ANTENNADIFFAREA 0.832300 ;
    PORT
      LAYER met2 ;
        RECT 69.090 178.100 69.370 178.380 ;
    END
  END prdata_16
  PIN prdata_17
    DIRECTION OUTPUT ;
    USE SIGNAL ;
    ANTENNAGATEAREA 0.560700 ;
    ANTENNADIFFAREA 0.863700 ;
    PORT
      LAYER met2 ;
        RECT 23.090 178.100 23.370 178.380 ;
    END
  END prdata_17
  PIN prdata_18
    DIRECTION OUTPUT ;
    USE SIGNAL ;
    ANTENNAGATEAREA 0.560700 ;
    ANTENNADIFFAREA 0.863700 ;
    PORT
      LAYER met2 ;
        RECT 67.250 0.000 67.530 0.280 ;
    END
  END prdata_18
  PIN prdata_19
    DIRECTION OUTPUT ;
    USE SIGNAL ;
    ANTENNAGATEAREA 0.560700 ;
    ANTENNADIFFAREA 0.863700 ;
    PORT
      LAYER met2 ;
        RECT 24.010 0.000 24.290 0.280 ;
    END
  END prdata_19
  PIN prdata_2
    DIRECTION OUTPUT ;
    USE SIGNAL ;
    ANTENNAGATEAREA 0.560700 ;
    ANTENNADIFFAREA 0.863700 ;
    PORT
      LAYER met2 ;
        RECT 101.290 0.000 101.570 0.280 ;
    END
  END prdata_2
  PIN prdata_20
    DIRECTION OUTPUT ;
    USE SIGNAL ;
    ANTENNAGATEAREA 0.560700 ;
    ANTENNADIFFAREA 0.863700 ;
    PORT
      LAYER met3 ;
        RECT 0.000 53.080 0.600 53.680 ;
    END
  END prdata_20
  PIN prdata_21
    DIRECTION OUTPUT ;
    USE SIGNAL ;
    ANTENNAGATEAREA 0.560700 ;
    ANTENNADIFFAREA 0.863700 ;
    PORT
      LAYER met3 ;
        RECT 0.000 70.760 0.600 71.360 ;
    END
  END prdata_21
  PIN prdata_22
    DIRECTION OUTPUT ;
    USE SIGNAL ;
    ANTENNAGATEAREA 0.560700 ;
    ANTENNADIFFAREA 0.863700 ;
    PORT
      LAYER met3 ;
        RECT 0.000 85.720 0.600 86.320 ;
    END
  END prdata_22
  PIN prdata_23
    DIRECTION OUTPUT ;
    USE SIGNAL ;
    ANTENNAGATEAREA 0.560700 ;
    ANTENNADIFFAREA 0.863700 ;
    PORT
      LAYER met3 ;
        RECT 167.060 156.440 167.660 157.040 ;
    END
  END prdata_23
  PIN prdata_24
    DIRECTION OUTPUT ;
    USE SIGNAL ;
    ANTENNAGATEAREA 0.560700 ;
    ANTENNADIFFAREA 0.863700 ;
    PORT
      LAYER met3 ;
        RECT 0.000 100.680 0.600 101.280 ;
    END
  END prdata_24
  PIN prdata_25
    DIRECTION OUTPUT ;
    USE SIGNAL ;
    ANTENNAGATEAREA 0.560700 ;
    ANTENNADIFFAREA 0.863700 ;
    PORT
      LAYER met3 ;
        RECT 0.000 138.760 0.600 139.360 ;
    END
  END prdata_25
  PIN prdata_26
    DIRECTION OUTPUT ;
    USE SIGNAL ;
    ANTENNAGATEAREA 0.560700 ;
    ANTENNADIFFAREA 0.863700 ;
    PORT
      LAYER met3 ;
        RECT 0.000 88.440 0.600 89.040 ;
    END
  END prdata_26
  PIN prdata_27
    DIRECTION OUTPUT ;
    USE SIGNAL ;
    ANTENNAGATEAREA 0.560700 ;
    ANTENNADIFFAREA 0.863700 ;
    PORT
      LAYER met2 ;
        RECT 49.770 178.100 50.050 178.380 ;
    END
  END prdata_27
  PIN prdata_28
    DIRECTION OUTPUT ;
    USE SIGNAL ;
    ANTENNAGATEAREA 0.560700 ;
    ANTENNADIFFAREA 0.863700 ;
    PORT
      LAYER met2 ;
        RECT 103.130 178.100 103.410 178.380 ;
    END
  END prdata_28
  PIN prdata_29
    DIRECTION OUTPUT ;
    USE SIGNAL ;
    ANTENNAGATEAREA 0.434700 ;
    ANTENNADIFFAREA 1.137600 ;
    PORT
      LAYER met2 ;
        RECT 93.010 178.100 93.290 178.380 ;
    END
  END prdata_29
  PIN prdata_3
    DIRECTION OUTPUT ;
    USE SIGNAL ;
    ANTENNAGATEAREA 0.560700 ;
    ANTENNADIFFAREA 0.863700 ;
    PORT
      LAYER met2 ;
        RECT 47.930 0.000 48.210 0.280 ;
    END
  END prdata_3
  PIN prdata_30
    DIRECTION OUTPUT ;
    USE SIGNAL ;
    ANTENNAGATEAREA 0.560700 ;
    ANTENNADIFFAREA 0.863700 ;
    PORT
      LAYER met3 ;
        RECT 167.060 95.240 167.660 95.840 ;
    END
  END prdata_30
  PIN prdata_31
    DIRECTION OUTPUT ;
    USE SIGNAL ;
    ANTENNAGATEAREA 0.560700 ;
    ANTENNADIFFAREA 0.863700 ;
    PORT
      LAYER met2 ;
        RECT 87.490 0.000 87.770 0.280 ;
    END
  END prdata_31
  PIN prdata_4
    DIRECTION OUTPUT ;
    USE SIGNAL ;
    ANTENNAGATEAREA 0.434700 ;
    ANTENNADIFFAREA 1.137600 ;
    PORT
      LAYER met2 ;
        RECT 120.610 0.000 120.890 0.280 ;
    END
  END prdata_4
  PIN prdata_5
    DIRECTION OUTPUT ;
    USE SIGNAL ;
    ANTENNAGATEAREA 0.560700 ;
    ANTENNADIFFAREA 0.863700 ;
    PORT
      LAYER met3 ;
        RECT 0.000 118.360 0.600 118.960 ;
    END
  END prdata_5
  PIN prdata_6
    DIRECTION OUTPUT ;
    USE SIGNAL ;
    ANTENNAGATEAREA 0.560700 ;
    ANTENNADIFFAREA 0.863700 ;
    PORT
      LAYER met2 ;
        RECT 85.650 0.000 85.930 0.280 ;
    END
  END prdata_6
  PIN prdata_7
    DIRECTION OUTPUT ;
    USE SIGNAL ;
    ANTENNAGATEAREA 0.434700 ;
    ANTENNADIFFAREA 1.137600 ;
    PORT
      LAYER met3 ;
        RECT 167.060 130.600 167.660 131.200 ;
    END
  END prdata_7
  PIN prdata_8
    DIRECTION OUTPUT ;
    USE SIGNAL ;
    ANTENNAGATEAREA 0.560700 ;
    ANTENNADIFFAREA 0.863700 ;
    PORT
      LAYER met3 ;
        RECT 167.060 118.360 167.660 118.960 ;
    END
  END prdata_8
  PIN prdata_9
    DIRECTION OUTPUT ;
    USE SIGNAL ;
    ANTENNAGATEAREA 0.434700 ;
    ANTENNADIFFAREA 1.137600 ;
    PORT
      LAYER met2 ;
        RECT 104.050 0.000 104.330 0.280 ;
    END
  END prdata_9
  PIN pready
    DIRECTION OUTPUT ;
    USE SIGNAL ;
    PORT
      LAYER met2 ;
        RECT 10.210 0.000 10.490 0.280 ;
    END
  END pready
  PIN psel
    DIRECTION INPUT ;
    USE SIGNAL ;
    ANTENNAGATEAREA 0.647700 ;
    ANTENNADIFFAREA 0.434700 ;
    PORT
      LAYER met3 ;
        RECT 167.060 43.560 167.660 44.160 ;
    END
  END psel
  PIN pslverr
    DIRECTION OUTPUT ;
    USE SIGNAL ;
    ANTENNAGATEAREA 0.434700 ;
    ANTENNADIFFAREA 0.775300 ;
    PORT
      LAYER met3 ;
        RECT 0.000 15.000 0.600 15.600 ;
    END
  END pslverr
  PIN pwdata_0
    DIRECTION INPUT ;
    USE SIGNAL ;
    ANTENNAGATEAREA 0.647700 ;
    ANTENNADIFFAREA 0.434700 ;
    PORT
      LAYER met2 ;
        RECT 91.170 0.000 91.450 0.280 ;
    END
  END pwdata_0
  PIN pwdata_1
    DIRECTION INPUT ;
    USE SIGNAL ;
    ANTENNAGATEAREA 0.647700 ;
    ANTENNADIFFAREA 0.434700 ;
    PORT
      LAYER met3 ;
        RECT 167.060 83.000 167.660 83.600 ;
    END
  END pwdata_1
  PIN pwdata_10
    DIRECTION INPUT ;
    USE SIGNAL ;
    ANTENNAGATEAREA 0.647700 ;
    ANTENNADIFFAREA 0.434700 ;
    PORT
      LAYER met3 ;
        RECT 0.000 66.680 0.600 67.280 ;
    END
  END pwdata_10
  PIN pwdata_11
    DIRECTION INPUT ;
    USE SIGNAL ;
    ANTENNAGATEAREA 0.647700 ;
    ANTENNADIFFAREA 0.434700 ;
    PORT
      LAYER met3 ;
        RECT 0.000 50.360 0.600 50.960 ;
    END
  END pwdata_11
  PIN pwdata_12
    DIRECTION INPUT ;
    USE SIGNAL ;
    ANTENNAGATEAREA 0.647700 ;
    ANTENNADIFFAREA 0.434700 ;
    PORT
      LAYER met2 ;
        RECT 24.930 0.000 25.210 0.280 ;
    END
  END pwdata_12
  PIN pwdata_13
    DIRECTION INPUT ;
    USE SIGNAL ;
    ANTENNAGATEAREA 0.647700 ;
    ANTENNADIFFAREA 0.434700 ;
    PORT
      LAYER met2 ;
        RECT 64.490 0.000 64.770 0.280 ;
    END
  END pwdata_13
  PIN pwdata_14
    DIRECTION INPUT ;
    USE SIGNAL ;
    ANTENNAGATEAREA 0.647700 ;
    ANTENNADIFFAREA 0.434700 ;
    PORT
      LAYER met2 ;
        RECT 41.490 178.100 41.770 178.380 ;
    END
  END pwdata_14
  PIN pwdata_15
    DIRECTION INPUT ;
    USE SIGNAL ;
    ANTENNAGATEAREA 0.647700 ;
    ANTENNADIFFAREA 0.434700 ;
    PORT
      LAYER met2 ;
        RECT 77.370 178.100 77.650 178.380 ;
    END
  END pwdata_15
  PIN pwdata_16
    DIRECTION INPUT ;
    USE SIGNAL ;
    ANTENNAGATEAREA 0.647700 ;
    ANTENNADIFFAREA 0.434700 ;
    PORT
      LAYER met3 ;
        RECT 167.060 25.880 167.660 26.480 ;
    END
  END pwdata_16
  PIN pwdata_17
    DIRECTION INPUT ;
    USE SIGNAL ;
    ANTENNAGATEAREA 0.647700 ;
    ANTENNADIFFAREA 0.434700 ;
    PORT
      LAYER met2 ;
        RECT 94.850 178.100 95.130 178.380 ;
    END
  END pwdata_17
  PIN pwdata_18
    DIRECTION INPUT ;
    USE SIGNAL ;
    ANTENNAGATEAREA 0.647700 ;
    ANTENNADIFFAREA 0.434700 ;
    PORT
      LAYER met3 ;
        RECT 167.060 47.640 167.660 48.240 ;
    END
  END pwdata_18
  PIN pwdata_19
    DIRECTION INPUT ;
    USE SIGNAL ;
    ANTENNAGATEAREA 0.647700 ;
    ANTENNADIFFAREA 0.434700 ;
    PORT
      LAYER met2 ;
        RECT 62.650 0.000 62.930 0.280 ;
    END
  END pwdata_19
  PIN pwdata_2
    DIRECTION INPUT ;
    USE SIGNAL ;
    ANTENNAGATEAREA 0.647700 ;
    ANTENNADIFFAREA 0.434700 ;
    PORT
      LAYER met2 ;
        RECT 100.370 178.100 100.650 178.380 ;
    END
  END pwdata_2
  PIN pwdata_20
    DIRECTION INPUT ;
    USE SIGNAL ;
    ANTENNAGATEAREA 0.647700 ;
    ANTENNADIFFAREA 0.434700 ;
    PORT
      LAYER met2 ;
        RECT 124.290 178.100 124.570 178.380 ;
    END
  END pwdata_20
  PIN pwdata_21
    DIRECTION INPUT ;
    USE SIGNAL ;
    ANTENNAGATEAREA 0.647700 ;
    ANTENNADIFFAREA 0.434700 ;
    PORT
      LAYER met2 ;
        RECT 83.810 178.100 84.090 178.380 ;
    END
  END pwdata_21
  PIN pwdata_22
    DIRECTION INPUT ;
    USE SIGNAL ;
    ANTENNAGATEAREA 0.647700 ;
    ANTENNADIFFAREA 0.434700 ;
    PORT
      LAYER met2 ;
        RECT 102.210 0.000 102.490 0.280 ;
    END
  END pwdata_22
  PIN pwdata_23
    DIRECTION INPUT ;
    USE SIGNAL ;
    ANTENNAGATEAREA 0.647700 ;
    ANTENNADIFFAREA 0.434700 ;
    PORT
      LAYER met3 ;
        RECT 167.060 112.920 167.660 113.520 ;
    END
  END pwdata_23
  PIN pwdata_24
    DIRECTION INPUT ;
    USE SIGNAL ;
    ANTENNAGATEAREA 0.647700 ;
    ANTENNADIFFAREA 0.434700 ;
    PORT
      LAYER met3 ;
        RECT 167.060 133.320 167.660 133.920 ;
    END
  END pwdata_24
  PIN pwdata_25
    DIRECTION INPUT ;
    USE SIGNAL ;
    ANTENNAGATEAREA 0.647700 ;
    ANTENNADIFFAREA 0.434700 ;
    PORT
      LAYER met2 ;
        RECT 81.970 0.000 82.250 0.280 ;
    END
  END pwdata_25
  PIN pwdata_26
    DIRECTION INPUT ;
    USE SIGNAL ;
    ANTENNAGATEAREA 0.647700 ;
    ANTENNADIFFAREA 0.434700 ;
    PORT
      LAYER met3 ;
        RECT 0.000 117.000 0.600 117.600 ;
    END
  END pwdata_26
  PIN pwdata_27
    DIRECTION INPUT ;
    USE SIGNAL ;
    ANTENNAGATEAREA 0.647700 ;
    ANTENNADIFFAREA 0.434700 ;
    PORT
      LAYER met2 ;
        RECT 118.770 0.000 119.050 0.280 ;
    END
  END pwdata_27
  PIN pwdata_28
    DIRECTION INPUT ;
    USE SIGNAL ;
    ANTENNAGATEAREA 0.647700 ;
    ANTENNADIFFAREA 0.434700 ;
    PORT
      LAYER met2 ;
        RECT 46.090 0.000 46.370 0.280 ;
    END
  END pwdata_28
  PIN pwdata_29
    DIRECTION INPUT ;
    USE SIGNAL ;
    ANTENNAGATEAREA 0.647700 ;
    ANTENNADIFFAREA 0.434700 ;
    PORT
      LAYER met3 ;
        RECT 167.060 53.080 167.660 53.680 ;
    END
  END pwdata_29
  PIN pwdata_3
    DIRECTION INPUT ;
    USE SIGNAL ;
    ANTENNAGATEAREA 0.647700 ;
    ANTENNADIFFAREA 0.434700 ;
    PORT
      LAYER met2 ;
        RECT 112.330 178.100 112.610 178.380 ;
    END
  END pwdata_3
  PIN pwdata_30
    DIRECTION INPUT ;
    USE SIGNAL ;
    ANTENNAGATEAREA 0.647700 ;
    ANTENNADIFFAREA 0.434700 ;
    PORT
      LAYER met3 ;
        RECT 167.060 91.160 167.660 91.760 ;
    END
  END pwdata_30
  PIN pwdata_31
    DIRECTION INPUT ;
    USE SIGNAL ;
    ANTENNAGATEAREA 0.647700 ;
    ANTENNADIFFAREA 0.434700 ;
    PORT
      LAYER met3 ;
        RECT 167.060 66.680 167.660 67.280 ;
    END
  END pwdata_31
  PIN pwdata_4
    DIRECTION INPUT ;
    USE SIGNAL ;
    ANTENNAGATEAREA 0.647700 ;
    ANTENNADIFFAREA 0.434700 ;
    PORT
      LAYER met2 ;
        RECT 61.730 178.100 62.010 178.380 ;
    END
  END pwdata_4
  PIN pwdata_5
    DIRECTION INPUT ;
    USE SIGNAL ;
    ANTENNAGATEAREA 0.647700 ;
    ANTENNADIFFAREA 0.434700 ;
    PORT
      LAYER met3 ;
        RECT 0.000 84.360 0.600 84.960 ;
    END
  END pwdata_5
  PIN pwdata_6
    DIRECTION INPUT ;
    USE SIGNAL ;
    ANTENNAGATEAREA 0.647700 ;
    ANTENNADIFFAREA 0.434700 ;
    PORT
      LAYER met3 ;
        RECT 0.000 134.680 0.600 135.280 ;
    END
  END pwdata_6
  PIN pwdata_7
    DIRECTION INPUT ;
    USE SIGNAL ;
    ANTENNAGATEAREA 0.647700 ;
    ANTENNADIFFAREA 0.434700 ;
    PORT
      LAYER met3 ;
        RECT 0.000 104.760 0.600 105.360 ;
    END
  END pwdata_7
  PIN pwdata_8
    DIRECTION INPUT ;
    USE SIGNAL ;
    ANTENNAGATEAREA 0.647700 ;
    ANTENNADIFFAREA 0.434700 ;
    PORT
      LAYER met2 ;
        RECT 149.130 178.100 149.410 178.380 ;
    END
  END pwdata_8
  PIN pwdata_9
    DIRECTION INPUT ;
    USE SIGNAL ;
    ANTENNAGATEAREA 0.647700 ;
    ANTENNADIFFAREA 0.434700 ;
    PORT
      LAYER met3 ;
        RECT 0.000 81.640 0.600 82.240 ;
    END
  END pwdata_9
  PIN pwrite
    DIRECTION INPUT ;
    USE SIGNAL ;
    ANTENNAGATEAREA 0.647700 ;
    ANTENNADIFFAREA 0.434700 ;
    PORT
      LAYER met3 ;
        RECT 167.060 44.920 167.660 45.520 ;
    END
  END pwrite
  PIN rst_n
    DIRECTION INPUT ;
    USE SIGNAL ;
    ANTENNAGATEAREA 0.647700 ;
    ANTENNADIFFAREA 0.434700 ;
    PORT
      LAYER met3 ;
        RECT 167.060 13.640 167.660 14.240 ;
    END
  END rst_n
  OBS
      LAYER nwell ;
        RECT 5.330 10.795 162.110 166.110 ;
      LAYER li1 ;
        RECT 5.520 10.795 161.920 166.005 ;
      LAYER met1 ;
        RECT 5.520 10.640 162.310 166.160 ;
      LAYER met2 ;
        RECT 5.610 177.820 22.810 178.310 ;
        RECT 23.650 177.820 34.770 178.310 ;
        RECT 35.610 177.820 36.610 178.310 ;
        RECT 37.450 177.820 41.210 178.310 ;
        RECT 42.050 177.820 49.490 178.310 ;
        RECT 50.330 177.820 54.090 178.310 ;
        RECT 54.930 177.820 56.850 178.310 ;
        RECT 57.690 177.820 59.610 178.310 ;
        RECT 60.450 177.820 61.450 178.310 ;
        RECT 62.290 177.820 68.810 178.310 ;
        RECT 69.650 177.820 70.650 178.310 ;
        RECT 71.490 177.820 71.570 178.310 ;
        RECT 72.410 177.820 72.490 178.310 ;
        RECT 73.330 177.820 75.250 178.310 ;
        RECT 76.090 177.820 77.090 178.310 ;
        RECT 77.930 177.820 78.010 178.310 ;
        RECT 78.850 177.820 80.770 178.310 ;
        RECT 81.610 177.820 83.530 178.310 ;
        RECT 84.370 177.820 84.450 178.310 ;
        RECT 85.290 177.820 86.290 178.310 ;
        RECT 87.130 177.820 87.210 178.310 ;
        RECT 88.050 177.820 91.810 178.310 ;
        RECT 92.650 177.820 92.730 178.310 ;
        RECT 93.570 177.820 94.570 178.310 ;
        RECT 95.410 177.820 98.250 178.310 ;
        RECT 99.090 177.820 99.170 178.310 ;
        RECT 100.010 177.820 100.090 178.310 ;
        RECT 100.930 177.820 102.850 178.310 ;
        RECT 103.690 177.820 103.770 178.310 ;
        RECT 104.610 177.820 105.610 178.310 ;
        RECT 106.450 177.820 112.050 178.310 ;
        RECT 112.890 177.820 115.730 178.310 ;
        RECT 116.570 177.820 116.650 178.310 ;
        RECT 117.490 177.820 119.410 178.310 ;
        RECT 120.250 177.820 124.010 178.310 ;
        RECT 124.850 177.820 133.210 178.310 ;
        RECT 134.050 177.820 134.130 178.310 ;
        RECT 134.970 177.820 148.850 178.310 ;
        RECT 149.690 177.820 162.280 178.310 ;
        RECT 5.610 0.560 162.280 177.820 ;
        RECT 6.170 0.070 6.250 0.560 ;
        RECT 7.090 0.070 7.170 0.560 ;
        RECT 8.010 0.070 8.090 0.560 ;
        RECT 8.930 0.070 9.010 0.560 ;
        RECT 9.850 0.070 9.930 0.560 ;
        RECT 10.770 0.070 23.730 0.560 ;
        RECT 24.570 0.070 24.650 0.560 ;
        RECT 25.490 0.070 33.850 0.560 ;
        RECT 34.690 0.070 34.770 0.560 ;
        RECT 35.610 0.070 43.970 0.560 ;
        RECT 44.810 0.070 45.810 0.560 ;
        RECT 46.650 0.070 47.650 0.560 ;
        RECT 48.490 0.070 52.250 0.560 ;
        RECT 53.090 0.070 58.690 0.560 ;
        RECT 59.530 0.070 62.370 0.560 ;
        RECT 63.210 0.070 63.290 0.560 ;
        RECT 64.130 0.070 64.210 0.560 ;
        RECT 65.050 0.070 66.970 0.560 ;
        RECT 67.810 0.070 67.890 0.560 ;
        RECT 68.730 0.070 70.650 0.560 ;
        RECT 71.490 0.070 75.250 0.560 ;
        RECT 76.090 0.070 76.170 0.560 ;
        RECT 77.010 0.070 80.770 0.560 ;
        RECT 81.610 0.070 81.690 0.560 ;
        RECT 82.530 0.070 85.370 0.560 ;
        RECT 86.210 0.070 86.290 0.560 ;
        RECT 87.130 0.070 87.210 0.560 ;
        RECT 88.050 0.070 88.130 0.560 ;
        RECT 88.970 0.070 89.050 0.560 ;
        RECT 89.890 0.070 89.970 0.560 ;
        RECT 90.810 0.070 90.890 0.560 ;
        RECT 91.730 0.070 99.170 0.560 ;
        RECT 100.010 0.070 101.010 0.560 ;
        RECT 101.850 0.070 101.930 0.560 ;
        RECT 102.770 0.070 103.770 0.560 ;
        RECT 104.610 0.070 106.530 0.560 ;
        RECT 107.370 0.070 113.890 0.560 ;
        RECT 114.730 0.070 116.650 0.560 ;
        RECT 117.490 0.070 118.490 0.560 ;
        RECT 119.330 0.070 120.330 0.560 ;
        RECT 121.170 0.070 124.930 0.560 ;
        RECT 125.770 0.070 132.290 0.560 ;
        RECT 133.130 0.070 135.050 0.560 ;
        RECT 135.890 0.070 162.280 0.560 ;
      LAYER met3 ;
        RECT 0.600 162.880 167.060 166.085 ;
        RECT 1.000 160.120 167.060 162.880 ;
        RECT 0.600 157.440 167.060 160.120 ;
        RECT 0.600 156.040 166.660 157.440 ;
        RECT 0.600 150.640 167.060 156.040 ;
        RECT 1.000 149.240 167.060 150.640 ;
        RECT 0.600 147.920 167.060 149.240 ;
        RECT 0.600 146.520 166.660 147.920 ;
        RECT 0.600 143.840 167.060 146.520 ;
        RECT 1.000 142.440 167.060 143.840 ;
        RECT 0.600 139.760 167.060 142.440 ;
        RECT 1.000 138.400 167.060 139.760 ;
        RECT 1.000 137.000 166.660 138.400 ;
        RECT 0.600 135.680 167.060 137.000 ;
        RECT 1.000 134.320 167.060 135.680 ;
        RECT 1.000 134.280 166.660 134.320 ;
        RECT 0.600 130.240 166.660 134.280 ;
        RECT 1.000 130.200 166.660 130.240 ;
        RECT 1.000 128.840 167.060 130.200 ;
        RECT 0.600 124.800 167.060 128.840 ;
        RECT 1.000 123.400 167.060 124.800 ;
        RECT 0.600 122.080 167.060 123.400 ;
        RECT 1.000 117.960 166.660 122.080 ;
        RECT 1.000 115.240 167.060 117.960 ;
        RECT 0.600 113.920 167.060 115.240 ;
        RECT 0.600 108.480 166.660 113.920 ;
        RECT 1.000 108.440 166.660 108.480 ;
        RECT 1.000 107.080 167.060 108.440 ;
        RECT 0.600 105.760 167.060 107.080 ;
        RECT 1.000 104.400 167.060 105.760 ;
        RECT 1.000 103.000 166.660 104.400 ;
        RECT 0.600 101.680 166.660 103.000 ;
        RECT 1.000 98.920 166.660 101.680 ;
        RECT 0.600 96.240 167.060 98.920 ;
        RECT 0.600 94.880 166.660 96.240 ;
        RECT 1.000 93.480 166.660 94.880 ;
        RECT 1.000 92.160 167.060 93.480 ;
        RECT 1.000 90.760 166.660 92.160 ;
        RECT 1.000 89.440 167.060 90.760 ;
        RECT 1.000 88.040 166.660 89.440 ;
        RECT 1.000 86.720 167.060 88.040 ;
        RECT 1.000 81.240 166.660 86.720 ;
        RECT 0.600 79.920 166.660 81.240 ;
        RECT 1.000 78.520 166.660 79.920 ;
        RECT 0.600 77.160 166.660 78.520 ;
        RECT 0.600 73.120 167.060 77.160 ;
        RECT 1.000 69.040 167.060 73.120 ;
        RECT 1.000 66.280 166.660 69.040 ;
        RECT 0.600 64.960 166.660 66.280 ;
        RECT 1.000 63.560 166.660 64.960 ;
        RECT 1.000 62.240 167.060 63.560 ;
        RECT 1.000 60.840 166.660 62.240 ;
        RECT 0.600 56.800 167.060 60.840 ;
        RECT 0.600 55.440 166.660 56.800 ;
        RECT 1.000 52.680 166.660 55.440 ;
        RECT 1.000 51.360 167.060 52.680 ;
        RECT 1.000 48.600 166.660 51.360 ;
        RECT 0.600 47.240 166.660 48.600 ;
        RECT 0.600 45.920 167.060 47.240 ;
        RECT 0.600 41.800 166.660 45.920 ;
        RECT 0.600 39.120 167.060 41.800 ;
        RECT 0.600 37.720 166.660 39.120 ;
        RECT 0.600 33.680 167.060 37.720 ;
        RECT 1.000 32.280 167.060 33.680 ;
        RECT 0.600 30.960 167.060 32.280 ;
        RECT 0.600 29.560 166.660 30.960 ;
        RECT 0.600 26.880 167.060 29.560 ;
        RECT 0.600 25.480 166.660 26.880 ;
        RECT 0.600 22.800 167.060 25.480 ;
        RECT 0.600 21.400 166.660 22.800 ;
        RECT 0.600 17.360 167.060 21.400 ;
        RECT 1.000 14.640 167.060 17.360 ;
        RECT 1.000 13.240 166.660 14.640 ;
        RECT 0.600 10.715 167.060 13.240 ;
      LAYER met4 ;
        RECT 17.775 19.215 20.640 154.185 ;
        RECT 23.040 19.215 23.940 154.185 ;
        RECT 26.340 19.215 157.945 154.185 ;
  END
END apb_gpio
END LIBRARY

